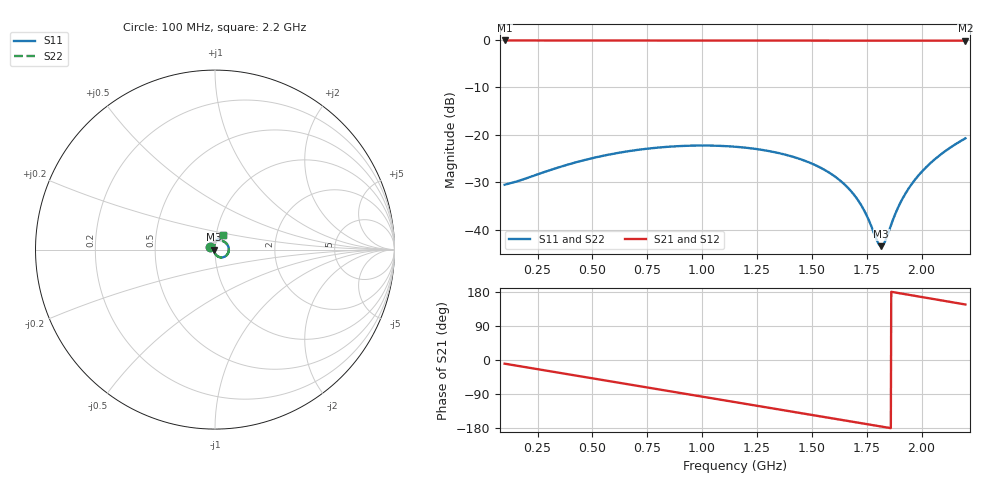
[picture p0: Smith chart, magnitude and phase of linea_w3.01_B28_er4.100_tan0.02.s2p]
! Chirptenna · simulación 3D de una microstrip de dos puertos (S12 = S21, S22 = S11 por simetría)
# HZ S RI R 50
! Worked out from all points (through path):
!   1101 points, 100 MHz to 2.2 GHz, reference 50 ohm
!   highest |S21| = -0.14 dB at 100 MHz (marker M1); lowest = -0.2 dB at 2.2 GHz (marker M2)
!   group delay of S21, straight-line fit = 269 ps
!   lowest |S11| = -43.5 dB at 1.816 GHz (marker M3), VSWR 1.01, Z = 49.3 - j0.0715 ohm
!   |S11| at or under -10 dB: start of sweep to end of sweep
!   |S22| runs from -43.5 to -20.7 dB; largest |S21 - S12| = 0
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1e8  -0.0253 0.0157  0.9702 -0.165  0.9702 -0.165  -0.0253 0.0157
2.699091e8  -0.0101 0.0384  0.8837 -0.4318  0.8837 -0.4318  -0.0101 0.0384
4.512727e8  0.0164 0.0506  0.7125 -0.6767  0.7125 -0.6767  0.0164 0.0506
6.307273e8  0.0452 0.047  0.4788 -0.8569  0.4788 -0.8569  0.0452 0.047
8.006364e8  0.0669 0.0301  0.2181 -0.9561  0.2181 -0.9561  0.0669 0.0301
9.743636e8  0.0769 0.00445  -0.066 -0.9778  -0.066 -0.9778  0.0769 0.00445
1.15e9  0.0715 -0.022  -0.3476 -0.9162  -0.3476 -0.9162  0.0715 -0.022
1.342818e9  0.05 -0.041  -0.6222 -0.7578  -0.6222 -0.7578  0.05 -0.041
1.501273e9  0.026 -0.0422  -0.8014 -0.5665  -0.8014 -0.5665  0.026 -0.0422
1.602455e9  0.0114 -0.035  -0.887 -0.4213  -0.887 -0.4213  0.0114 -0.035
1.682636e9  0.00193 -0.0248  -0.9366 -0.2967  -0.9366 -0.2967  0.00193 -0.0248
1.734182e9  -0.00263 -0.0165  -0.9592 -0.2132  -0.9592 -0.2132  -0.00263 -0.0165
1.759e9  -0.00431 -0.012  -0.9675 -0.1723  -0.9675 -0.1723  -0.00431 -0.012
1.799091e9  -0.0062 -0.00423  -0.9772 -0.1055  -0.9772 -0.1055  -0.0062 -0.00423
1.816273e9  -0.00668 -0.000724  -0.9799 -0.0767  -0.9799 -0.0767  -0.00668 -0.000724
1.831545e9  -0.00693 0.00248  -0.9816 -0.051  -0.9816 -0.051  -0.00693 0.00248
1.850636e9  -0.007 0.00657  -0.9827 -0.0187  -0.9827 -0.0187  -0.007 0.00657
1.879273e9  -0.00658 0.0129  -0.9824 0.0296  -0.9824 0.0296  -0.00658 0.0129
1.907909e9  -0.00551 0.0193  -0.9797 0.078  -0.9797 0.078  -0.00551 0.0193
1.978545e9  4.59e-05 0.0356  -0.9626 0.1964  -0.9626 0.1964  4.59e-05 0.0356
2.077818e9  0.0152 0.0575  -0.9138 0.3575  -0.9138 0.3575  0.0152 0.0575
2.2e9  0.0455 0.0796  -0.8162 0.5404  -0.8162 0.5404  0.0455 0.0796
